VERSION 5.4 ;
NAMESCASESENSITIVE ON ;
BUSBITCHARS "[]" ;
DIVIDERCHAR "/" ;
UNITS
  DATABASE MICRONS 2000 ;
END UNITS
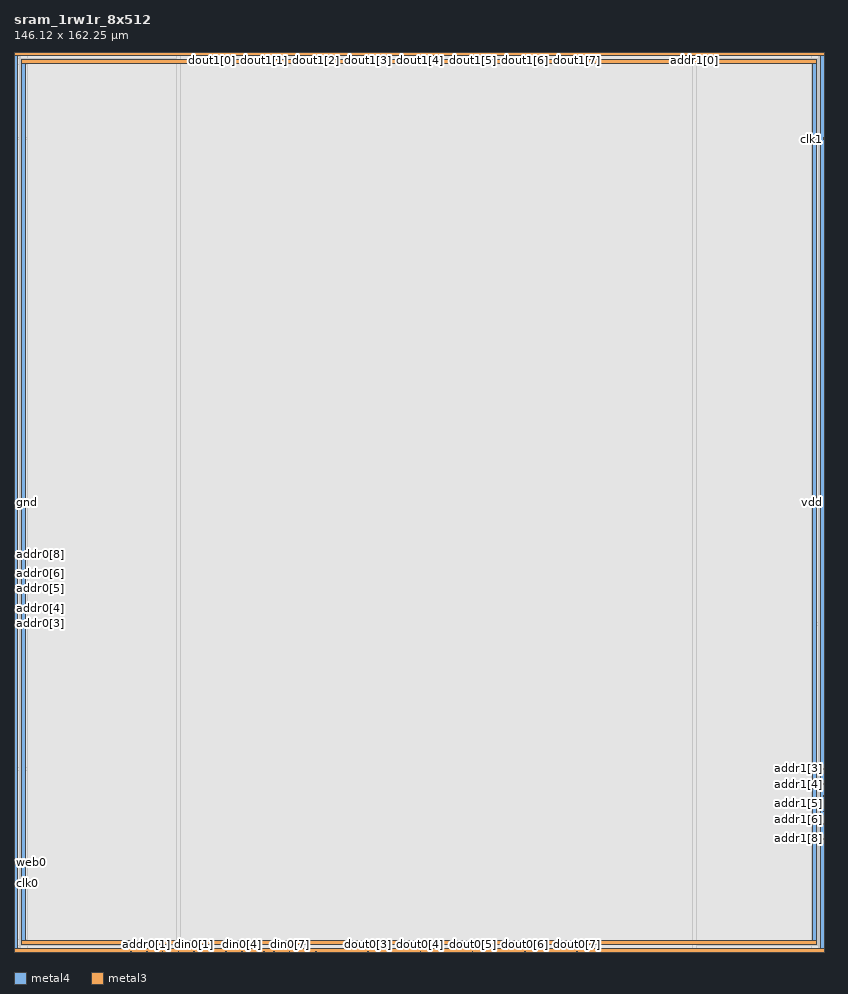
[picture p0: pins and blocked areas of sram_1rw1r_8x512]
MACRO sram_1rw1r_8x512
   CLASS BLOCK ;
   SIZE 146.12 BY 162.25 ;
   SYMMETRY X Y R90 ;
   PIN din0[0]
      DIRECTION INPUT ;
      PORT
         LAYER metal4 ;
         RECT  29.5775 0.0 29.7175 0.14 ;
      END
   END din0[0]
   PIN din0[1]
      DIRECTION INPUT ;
      PORT
         LAYER metal4 ;
         RECT  32.4375 0.0 32.5775 0.14 ;
      END
   END din0[1]
   PIN din0[2]
      DIRECTION INPUT ;
      PORT
         LAYER metal4 ;
         RECT  35.2975 0.0 35.4375 0.14 ;
      END
   END din0[2]
   PIN din0[3]
      DIRECTION INPUT ;
      PORT
         LAYER metal4 ;
         RECT  38.1575 0.0 38.2975 0.14 ;
      END
   END din0[3]
   PIN din0[4]
      DIRECTION INPUT ;
      PORT
         LAYER metal4 ;
         RECT  41.0175 0.0 41.1575 0.14 ;
      END
   END din0[4]
   PIN din0[5]
      DIRECTION INPUT ;
      PORT
         LAYER metal4 ;
         RECT  43.8775 0.0 44.0175 0.14 ;
      END
   END din0[5]
   PIN din0[6]
      DIRECTION INPUT ;
      PORT
         LAYER metal4 ;
         RECT  46.7375 0.0 46.8775 0.14 ;
      END
   END din0[6]
   PIN din0[7]
      DIRECTION INPUT ;
      PORT
         LAYER metal4 ;
         RECT  49.5975 0.0 49.7375 0.14 ;
      END
   END din0[7]
   PIN addr0[0]
      DIRECTION INPUT ;
      PORT
         LAYER metal4 ;
         RECT  20.9975 0.0 21.1375 0.14 ;
      END
   END addr0[0]
   PIN addr0[1]
      DIRECTION INPUT ;
      PORT
         LAYER metal4 ;
         RECT  23.8575 0.0 23.9975 0.14 ;
      END
   END addr0[1]
   PIN addr0[2]
      DIRECTION INPUT ;
      PORT
         LAYER metal4 ;
         RECT  26.7175 0.0 26.8575 0.14 ;
      END
   END addr0[2]
   PIN addr0[3]
      DIRECTION INPUT ;
      PORT
         LAYER metal3 ;
         RECT  0.0 59.07 0.14 59.21 ;
      END
   END addr0[3]
   PIN addr0[4]
      DIRECTION INPUT ;
      PORT
         LAYER metal3 ;
         RECT  0.0 61.8 0.14 61.94 ;
      END
   END addr0[4]
   PIN addr0[5]
      DIRECTION INPUT ;
      PORT
         LAYER metal3 ;
         RECT  0.0 64.01 0.14 64.15 ;
      END
   END addr0[5]
   PIN addr0[6]
      DIRECTION INPUT ;
      PORT
         LAYER metal3 ;
         RECT  0.0 66.74 0.14 66.88 ;
      END
   END addr0[6]
   PIN addr0[7]
      DIRECTION INPUT ;
      PORT
         LAYER metal3 ;
         RECT  0.0 68.95 0.14 69.09 ;
      END
   END addr0[7]
   PIN addr0[8]
      DIRECTION INPUT ;
      PORT
         LAYER metal3 ;
         RECT  0.0 71.68 0.14 71.82 ;
      END
   END addr0[8]
   PIN addr1[0]
      DIRECTION INPUT ;
      PORT
         LAYER metal4 ;
         RECT  122.6775 162.11 122.8175 162.25 ;
      END
   END addr1[0]
   PIN addr1[1]
      DIRECTION INPUT ;
      PORT
         LAYER metal4 ;
         RECT  119.8175 162.11 119.9575 162.25 ;
      END
   END addr1[1]
   PIN addr1[2]
      DIRECTION INPUT ;
      PORT
         LAYER metal4 ;
         RECT  116.9575 162.11 117.0975 162.25 ;
      END
   END addr1[2]
   PIN addr1[3]
      DIRECTION INPUT ;
      PORT
         LAYER metal3 ;
         RECT  145.98 32.94 146.12 33.08 ;
      END
   END addr1[3]
   PIN addr1[4]
      DIRECTION INPUT ;
      PORT
         LAYER metal3 ;
         RECT  145.98 30.21 146.12 30.35 ;
      END
   END addr1[4]
   PIN addr1[5]
      DIRECTION INPUT ;
      PORT
         LAYER metal3 ;
         RECT  145.98 28.0 146.12 28.14 ;
      END
   END addr1[5]
   PIN addr1[6]
      DIRECTION INPUT ;
      PORT
         LAYER metal3 ;
         RECT  145.98 25.27 146.12 25.41 ;
      END
   END addr1[6]
   PIN addr1[7]
      DIRECTION INPUT ;
      PORT
         LAYER metal3 ;
         RECT  145.98 23.06 146.12 23.2 ;
      END
   END addr1[7]
   PIN addr1[8]
      DIRECTION INPUT ;
      PORT
         LAYER metal3 ;
         RECT  145.98 20.33 146.12 20.47 ;
      END
   END addr1[8]
   PIN csb0
      DIRECTION INPUT ;
      PORT
         LAYER metal3 ;
         RECT  0.0 12.01 0.14 12.15 ;
      END
   END csb0
   PIN csb1
      DIRECTION INPUT ;
      PORT
         LAYER metal3 ;
         RECT  145.98 146.64 146.12 146.78 ;
      END
   END csb1
   PIN web0
      DIRECTION INPUT ;
      PORT
         LAYER metal3 ;
         RECT  0.0 14.74 0.14 14.88 ;
      END
   END web0
   PIN clk0
      DIRECTION INPUT ;
      PORT
         LAYER metal3 ;
         RECT  0.0 12.245 0.14 12.385 ;
      END
   END clk0
   PIN clk1
      DIRECTION INPUT ;
      PORT
         LAYER metal3 ;
         RECT  145.98 146.405 146.12 146.545 ;
      END
   END clk1
   PIN dout0[0]
      DIRECTION OUTPUT ;
      PORT
         LAYER metal4 ;
         RECT  35.5975 0.0 35.7375 0.14 ;
      END
   END dout0[0]
   PIN dout0[1]
      DIRECTION OUTPUT ;
      PORT
         LAYER metal4 ;
         RECT  44.9975 0.0 45.1375 0.14 ;
      END
   END dout0[1]
   PIN dout0[2]
      DIRECTION OUTPUT ;
      PORT
         LAYER metal4 ;
         RECT  54.3975 0.0 54.5375 0.14 ;
      END
   END dout0[2]
   PIN dout0[3]
      DIRECTION OUTPUT ;
      PORT
         LAYER metal4 ;
         RECT  63.7975 0.0 63.9375 0.14 ;
      END
   END dout0[3]
   PIN dout0[4]
      DIRECTION OUTPUT ;
      PORT
         LAYER metal4 ;
         RECT  73.1975 0.0 73.3375 0.14 ;
      END
   END dout0[4]
   PIN dout0[5]
      DIRECTION OUTPUT ;
      PORT
         LAYER metal4 ;
         RECT  82.5975 0.0 82.7375 0.14 ;
      END
   END dout0[5]
   PIN dout0[6]
      DIRECTION OUTPUT ;
      PORT
         LAYER metal4 ;
         RECT  91.9975 0.0 92.1375 0.14 ;
      END
   END dout0[6]
   PIN dout0[7]
      DIRECTION OUTPUT ;
      PORT
         LAYER metal4 ;
         RECT  101.3975 0.0 101.5375 0.14 ;
      END
   END dout0[7]
   PIN dout1[0]
      DIRECTION OUTPUT ;
      PORT
         LAYER metal4 ;
         RECT  35.5975 162.11 35.7375 162.25 ;
      END
   END dout1[0]
   PIN dout1[1]
      DIRECTION OUTPUT ;
      PORT
         LAYER metal4 ;
         RECT  44.9975 162.11 45.1375 162.25 ;
      END
   END dout1[1]
   PIN dout1[2]
      DIRECTION OUTPUT ;
      PORT
         LAYER metal4 ;
         RECT  54.3975 162.11 54.5375 162.25 ;
      END
   END dout1[2]
   PIN dout1[3]
      DIRECTION OUTPUT ;
      PORT
         LAYER metal4 ;
         RECT  63.7975 162.11 63.9375 162.25 ;
      END
   END dout1[3]
   PIN dout1[4]
      DIRECTION OUTPUT ;
      PORT
         LAYER metal4 ;
         RECT  73.1975 162.11 73.3375 162.25 ;
      END
   END dout1[4]
   PIN dout1[5]
      DIRECTION OUTPUT ;
      PORT
         LAYER metal4 ;
         RECT  82.5975 162.11 82.7375 162.25 ;
      END
   END dout1[5]
   PIN dout1[6]
      DIRECTION OUTPUT ;
      PORT
         LAYER metal4 ;
         RECT  91.9975 162.11 92.1375 162.25 ;
      END
   END dout1[6]
   PIN dout1[7]
      DIRECTION OUTPUT ;
      PORT
         LAYER metal4 ;
         RECT  101.3975 162.11 101.5375 162.25 ;
      END
   END dout1[7]
   PIN vdd
      DIRECTION INOUT ;
      USE POWER ; 
      SHAPE ABUTMENT ; 
      PORT
         LAYER metal4 ;
         RECT  145.42 0.0 146.12 162.25 ;
         LAYER metal4 ;
         RECT  0.0 0.0 0.7 162.25 ;
         LAYER metal3 ;
         RECT  0.0 0.0 146.12 0.7 ;
         LAYER metal3 ;
         RECT  0.0 161.55 146.12 162.25 ;
      END
   END vdd
   PIN gnd
      DIRECTION INOUT ;
      USE GROUND ; 
      SHAPE ABUTMENT ; 
      PORT
         LAYER metal4 ;
         RECT  1.4 1.4 2.1 160.85 ;
         LAYER metal3 ;
         RECT  1.4 1.4 144.72 2.1 ;
         LAYER metal4 ;
         RECT  144.02 1.4 144.72 160.85 ;
         LAYER metal3 ;
         RECT  1.4 160.15 144.72 160.85 ;
      END
   END gnd
   OBS
   LAYER  metal1 ;
      RECT  0.14 0.14 145.98 162.11 ;
   LAYER  metal2 ;
      RECT  0.14 0.14 145.98 162.11 ;
   LAYER  metal3 ;
      RECT  0.28 58.93 145.98 59.35 ;
      RECT  0.14 59.35 0.28 61.66 ;
      RECT  0.14 62.08 0.28 63.87 ;
      RECT  0.14 64.29 0.28 66.6 ;
      RECT  0.14 67.02 0.28 68.81 ;
      RECT  0.14 69.23 0.28 71.54 ;
      RECT  0.28 32.8 145.84 33.22 ;
      RECT  0.28 33.22 145.84 58.93 ;
      RECT  145.84 33.22 145.98 58.93 ;
      RECT  145.84 30.49 145.98 32.8 ;
      RECT  145.84 28.28 145.98 30.07 ;
      RECT  145.84 25.55 145.98 27.86 ;
      RECT  145.84 23.34 145.98 25.13 ;
      RECT  145.84 20.61 145.98 22.92 ;
      RECT  0.28 59.35 145.84 146.5 ;
      RECT  0.28 146.5 145.84 146.92 ;
      RECT  0.14 15.02 0.28 58.93 ;
      RECT  0.14 12.525 0.28 14.6 ;
      RECT  145.84 59.35 145.98 146.265 ;
      RECT  145.84 0.84 145.98 20.19 ;
      RECT  0.14 0.84 0.28 11.87 ;
      RECT  0.14 71.96 0.28 161.41 ;
      RECT  145.84 146.92 145.98 161.41 ;
      RECT  0.28 0.84 1.26 1.26 ;
      RECT  0.28 1.26 1.26 2.24 ;
      RECT  0.28 2.24 1.26 32.8 ;
      RECT  1.26 0.84 144.86 1.26 ;
      RECT  1.26 2.24 144.86 32.8 ;
      RECT  144.86 0.84 145.84 1.26 ;
      RECT  144.86 1.26 145.84 2.24 ;
      RECT  144.86 2.24 145.84 32.8 ;
      RECT  0.28 146.92 1.26 160.01 ;
      RECT  0.28 160.01 1.26 160.99 ;
      RECT  0.28 160.99 1.26 161.41 ;
      RECT  1.26 146.92 144.86 160.01 ;
      RECT  1.26 160.99 144.86 161.41 ;
      RECT  144.86 146.92 145.84 160.01 ;
      RECT  144.86 160.01 145.84 160.99 ;
      RECT  144.86 160.99 145.84 161.41 ;
   LAYER  metal4 ;
      RECT  29.2975 0.42 29.9975 162.11 ;
      RECT  29.9975 0.14 32.1575 0.42 ;
      RECT  32.8575 0.14 35.0175 0.42 ;
      RECT  38.5775 0.14 40.7375 0.42 ;
      RECT  41.4375 0.14 43.5975 0.42 ;
      RECT  47.1575 0.14 49.3175 0.42 ;
      RECT  21.4175 0.14 23.5775 0.42 ;
      RECT  24.2775 0.14 26.4375 0.42 ;
      RECT  27.1375 0.14 29.2975 0.42 ;
      RECT  29.9975 0.42 122.3975 161.83 ;
      RECT  122.3975 0.42 123.0975 161.83 ;
      RECT  120.2375 161.83 122.3975 162.11 ;
      RECT  117.3775 161.83 119.5375 162.11 ;
      RECT  36.0175 0.14 37.8775 0.42 ;
      RECT  44.2975 0.14 44.7175 0.42 ;
      RECT  45.4175 0.14 46.4575 0.42 ;
      RECT  50.0175 0.14 54.1175 0.42 ;
      RECT  54.8175 0.14 63.5175 0.42 ;
      RECT  64.2175 0.14 72.9175 0.42 ;
      RECT  73.6175 0.14 82.3175 0.42 ;
      RECT  83.0175 0.14 91.7175 0.42 ;
      RECT  92.4175 0.14 101.1175 0.42 ;
      RECT  29.9975 161.83 35.3175 162.11 ;
      RECT  36.0175 161.83 44.7175 162.11 ;
      RECT  45.4175 161.83 54.1175 162.11 ;
      RECT  54.8175 161.83 63.5175 162.11 ;
      RECT  64.2175 161.83 72.9175 162.11 ;
      RECT  73.6175 161.83 82.3175 162.11 ;
      RECT  83.0175 161.83 91.7175 162.11 ;
      RECT  92.4175 161.83 101.1175 162.11 ;
      RECT  101.8175 161.83 116.6775 162.11 ;
      RECT  123.0975 161.83 145.14 162.11 ;
      RECT  101.8175 0.14 145.14 0.42 ;
      RECT  0.98 0.14 20.7175 0.42 ;
      RECT  0.98 0.42 1.12 1.12 ;
      RECT  0.98 1.12 1.12 161.13 ;
      RECT  0.98 161.13 1.12 162.11 ;
      RECT  1.12 0.42 2.38 1.12 ;
      RECT  1.12 161.13 2.38 162.11 ;
      RECT  2.38 0.42 29.2975 1.12 ;
      RECT  2.38 1.12 29.2975 161.13 ;
      RECT  2.38 161.13 29.2975 162.11 ;
      RECT  123.0975 0.42 143.74 1.12 ;
      RECT  123.0975 1.12 143.74 161.13 ;
      RECT  123.0975 161.13 143.74 161.83 ;
      RECT  143.74 0.42 145.0 1.12 ;
      RECT  143.74 161.13 145.0 161.83 ;
      RECT  145.0 0.42 145.14 1.12 ;
      RECT  145.0 1.12 145.14 161.13 ;
      RECT  145.0 161.13 145.14 161.83 ;
   END
END    sram_1rw1r_8x512
END    LIBRARY
